VERSION 5.4 ;
NAMESCASESENSITIVE ON ;
BUSBITCHARS "[]" ;
DIVIDERCHAR "/" ;
UNITS
  DATABASE MICRONS 2000 ;
END UNITS
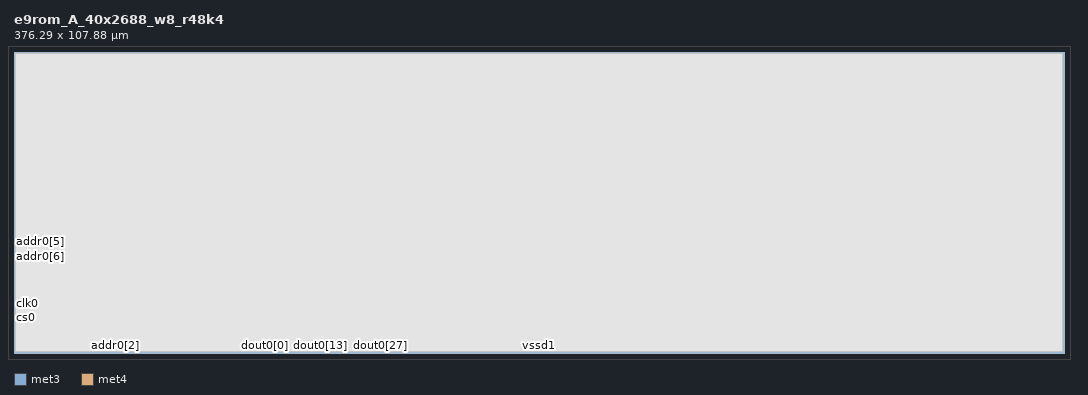
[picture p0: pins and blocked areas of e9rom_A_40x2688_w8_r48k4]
MACRO e9rom_A_40x2688_w8_r48k4
   CLASS BLOCK ;
   SIZE 376.29 BY 107.88 ;
   SYMMETRY X Y R90 ;
   PIN clk0
      DIRECTION INPUT ;
      PORT
         LAYER met3 ;
         RECT  -7.48 17.71 -7.1 18.09 ;
      END
   END clk0
   PIN cs0
      DIRECTION INPUT ;
      PORT
         LAYER met3 ;
         RECT  -7.48 12.675 -7.1 13.055 ;
      END
   END cs0
   PIN addr0[0]
      DIRECTION INPUT ;
      PORT
         LAYER met4 ;
         RECT  32.19 -7.48 32.57 -7.1 ;
      END
   END addr0[0]
   PIN addr0[1]
      DIRECTION INPUT ;
      PORT
         LAYER met4 ;
         RECT  34.23 -7.48 34.61 -7.1 ;
      END
   END addr0[1]
   PIN addr0[2]
      DIRECTION INPUT ;
      PORT
         LAYER met4 ;
         RECT  36.27 -7.48 36.65 -7.1 ;
      END
   END addr0[2]
   PIN addr0[3]
      DIRECTION INPUT ;
      PORT
         LAYER met3 ;
         RECT  -7.48 38.39 -7.1 38.77 ;
      END
   END addr0[3]
   PIN addr0[4]
      DIRECTION INPUT ;
      PORT
         LAYER met3 ;
         RECT  -7.48 39.135 -7.1 39.515 ;
      END
   END addr0[4]
   PIN addr0[5]
      DIRECTION INPUT ;
      PORT
         LAYER met3 ;
         RECT  -7.48 39.825 -7.1 40.205 ;
      END
   END addr0[5]
   PIN addr0[6]
      DIRECTION INPUT ;
      PORT
         LAYER met3 ;
         RECT  -7.48 36.92 -7.1 37.3 ;
      END
   END addr0[6]
   PIN addr0[7]
      DIRECTION INPUT ;
      PORT
         LAYER met3 ;
         RECT  -7.48 40.515 -7.1 40.895 ;
      END
   END addr0[7]
   PIN addr0[8]
      DIRECTION INPUT ;
      PORT
         LAYER met3 ;
         RECT  -7.48 36.23 -7.1 36.61 ;
      END
   END addr0[8]
   PIN dout0[0]
      DIRECTION OUTPUT ;
      PORT
         LAYER met4 ;
         RECT  89.635 -7.48 90.015 -7.1 ;
      END
   END dout0[0]
   PIN dout0[1]
      DIRECTION OUTPUT ;
      PORT
         LAYER met4 ;
         RECT  91.175 -7.48 91.555 -7.1 ;
      END
   END dout0[1]
   PIN dout0[2]
      DIRECTION OUTPUT ;
      PORT
         LAYER met4 ;
         RECT  92.715 -7.48 93.095 -7.1 ;
      END
   END dout0[2]
   PIN dout0[3]
      DIRECTION OUTPUT ;
      PORT
         LAYER met4 ;
         RECT  94.255 -7.48 94.635 -7.1 ;
      END
   END dout0[3]
   PIN dout0[4]
      DIRECTION OUTPUT ;
      PORT
         LAYER met4 ;
         RECT  95.795 -7.48 96.175 -7.1 ;
      END
   END dout0[4]
   PIN dout0[5]
      DIRECTION OUTPUT ;
      PORT
         LAYER met4 ;
         RECT  97.335 -7.48 97.715 -7.1 ;
      END
   END dout0[5]
   PIN dout0[6]
      DIRECTION OUTPUT ;
      PORT
         LAYER met4 ;
         RECT  98.875 -7.48 99.255 -7.1 ;
      END
   END dout0[6]
   PIN dout0[7]
      DIRECTION OUTPUT ;
      PORT
         LAYER met4 ;
         RECT  100.415 -7.48 100.795 -7.1 ;
      END
   END dout0[7]
   PIN dout0[8]
      DIRECTION OUTPUT ;
      PORT
         LAYER met4 ;
         RECT  101.955 -7.48 102.335 -7.1 ;
      END
   END dout0[8]
   PIN dout0[9]
      DIRECTION OUTPUT ;
      PORT
         LAYER met4 ;
         RECT  103.495 -7.48 103.875 -7.1 ;
      END
   END dout0[9]
   PIN dout0[10]
      DIRECTION OUTPUT ;
      PORT
         LAYER met4 ;
         RECT  105.035 -7.48 105.415 -7.1 ;
      END
   END dout0[10]
   PIN dout0[11]
      DIRECTION OUTPUT ;
      PORT
         LAYER met4 ;
         RECT  106.575 -7.48 106.955 -7.1 ;
      END
   END dout0[11]
   PIN dout0[12]
      DIRECTION OUTPUT ;
      PORT
         LAYER met4 ;
         RECT  108.115 -7.48 108.495 -7.1 ;
      END
   END dout0[12]
   PIN dout0[13]
      DIRECTION OUTPUT ;
      PORT
         LAYER met4 ;
         RECT  109.655 -7.48 110.035 -7.1 ;
      END
   END dout0[13]
   PIN dout0[14]
      DIRECTION OUTPUT ;
      PORT
         LAYER met4 ;
         RECT  111.195 -7.48 111.575 -7.1 ;
      END
   END dout0[14]
   PIN dout0[15]
      DIRECTION OUTPUT ;
      PORT
         LAYER met4 ;
         RECT  112.735 -7.48 113.115 -7.1 ;
      END
   END dout0[15]
   PIN dout0[16]
      DIRECTION OUTPUT ;
      PORT
         LAYER met4 ;
         RECT  114.275 -7.48 114.655 -7.1 ;
      END
   END dout0[16]
   PIN dout0[17]
      DIRECTION OUTPUT ;
      PORT
         LAYER met4 ;
         RECT  115.815 -7.48 116.195 -7.1 ;
      END
   END dout0[17]
   PIN dout0[18]
      DIRECTION OUTPUT ;
      PORT
         LAYER met4 ;
         RECT  117.355 -7.48 117.735 -7.1 ;
      END
   END dout0[18]
   PIN dout0[19]
      DIRECTION OUTPUT ;
      PORT
         LAYER met4 ;
         RECT  118.895 -7.48 119.275 -7.1 ;
      END
   END dout0[19]
   PIN dout0[20]
      DIRECTION OUTPUT ;
      PORT
         LAYER met4 ;
         RECT  120.435 -7.48 120.815 -7.1 ;
      END
   END dout0[20]
   PIN dout0[21]
      DIRECTION OUTPUT ;
      PORT
         LAYER met4 ;
         RECT  121.975 -7.48 122.355 -7.1 ;
      END
   END dout0[21]
   PIN dout0[22]
      DIRECTION OUTPUT ;
      PORT
         LAYER met4 ;
         RECT  123.515 -7.48 123.895 -7.1 ;
      END
   END dout0[22]
   PIN dout0[23]
      DIRECTION OUTPUT ;
      PORT
         LAYER met4 ;
         RECT  125.055 -7.48 125.435 -7.1 ;
      END
   END dout0[23]
   PIN dout0[24]
      DIRECTION OUTPUT ;
      PORT
         LAYER met4 ;
         RECT  126.595 -7.48 126.975 -7.1 ;
      END
   END dout0[24]
   PIN dout0[25]
      DIRECTION OUTPUT ;
      PORT
         LAYER met4 ;
         RECT  128.135 -7.48 128.515 -7.1 ;
      END
   END dout0[25]
   PIN dout0[26]
      DIRECTION OUTPUT ;
      PORT
         LAYER met4 ;
         RECT  129.675 -7.48 130.055 -7.1 ;
      END
   END dout0[26]
   PIN dout0[27]
      DIRECTION OUTPUT ;
      PORT
         LAYER met4 ;
         RECT  131.215 -7.48 131.595 -7.1 ;
      END
   END dout0[27]
   PIN dout0[28]
      DIRECTION OUTPUT ;
      PORT
         LAYER met4 ;
         RECT  132.755 -7.48 133.135 -7.1 ;
      END
   END dout0[28]
   PIN dout0[29]
      DIRECTION OUTPUT ;
      PORT
         LAYER met4 ;
         RECT  134.295 -7.48 134.675 -7.1 ;
      END
   END dout0[29]
   PIN dout0[30]
      DIRECTION OUTPUT ;
      PORT
         LAYER met4 ;
         RECT  135.835 -7.48 136.215 -7.1 ;
      END
   END dout0[30]
   PIN dout0[31]
      DIRECTION OUTPUT ;
      PORT
         LAYER met4 ;
         RECT  137.375 -7.48 137.755 -7.1 ;
      END
   END dout0[31]
   PIN dout0[32]
      DIRECTION OUTPUT ;
      PORT
         LAYER met4 ;
         RECT  138.915 -7.48 139.295 -7.1 ;
      END
   END dout0[32]
   PIN dout0[33]
      DIRECTION OUTPUT ;
      PORT
         LAYER met4 ;
         RECT  140.455 -7.48 140.835 -7.1 ;
      END
   END dout0[33]
   PIN dout0[34]
      DIRECTION OUTPUT ;
      PORT
         LAYER met4 ;
         RECT  141.995 -7.48 142.375 -7.1 ;
      END
   END dout0[34]
   PIN dout0[35]
      DIRECTION OUTPUT ;
      PORT
         LAYER met4 ;
         RECT  143.535 -7.48 143.915 -7.1 ;
      END
   END dout0[35]
   PIN dout0[36]
      DIRECTION OUTPUT ;
      PORT
         LAYER met4 ;
         RECT  145.075 -7.48 145.455 -7.1 ;
      END
   END dout0[36]
   PIN dout0[37]
      DIRECTION OUTPUT ;
      PORT
         LAYER met4 ;
         RECT  146.615 -7.48 146.995 -7.1 ;
      END
   END dout0[37]
   PIN dout0[38]
      DIRECTION OUTPUT ;
      PORT
         LAYER met4 ;
         RECT  148.155 -7.48 148.535 -7.1 ;
      END
   END dout0[38]
   PIN dout0[39]
      DIRECTION OUTPUT ;
      PORT
         LAYER met4 ;
         RECT  151.73 -7.48 152.11 -7.1 ;
      END
   END dout0[39]
   PIN vccd1
      DIRECTION INOUT ;
      USE POWER ; 
      SHAPE ABUTMENT ; 
      PORT
         LAYER met3 ;
         RECT  -7.48 -7.48 383.77 -5.74 ;
         LAYER met4 ;
         RECT  382.03 -7.48 383.77 115.36 ;
         LAYER met3 ;
         RECT  -7.48 113.62 383.77 115.36 ;
         LAYER met4 ;
         RECT  -7.48 -7.48 -5.74 115.36 ;
      END
   END vccd1
   PIN vssd1
      DIRECTION INOUT ;
      USE GROUND ; 
      SHAPE ABUTMENT ; 
      PORT
         LAYER met4 ;
         RECT  378.55 -4.0 380.29 111.88 ;
         LAYER met3 ;
         RECT  -4.0 110.14 380.29 111.88 ;
         LAYER met4 ;
         RECT  -4.0 -4.0 -2.26 111.88 ;
         LAYER met3 ;
         RECT  -4.0 -4.0 380.29 -2.26 ;
      END
   END vssd1
   OBS
   LAYER  met1 ;
      RECT  0.62 0.62 375.67 107.26 ;
   LAYER  met2 ;
      RECT  0.62 0.62 375.67 107.26 ;
   LAYER  met3 ;
      RECT  0.62 0.62 375.67 107.26 ;
   LAYER  met4 ;
      RECT  0.62 0.62 375.67 107.26 ;
   END
END    e9rom_A_40x2688_w8_r48k4
END    LIBRARY
